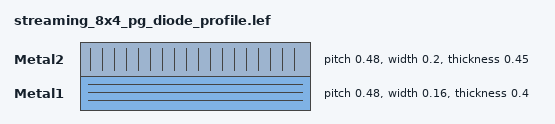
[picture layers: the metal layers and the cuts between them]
LAYER Metal1
  TYPE		ROUTING ;
  DIRECTION	HORIZONTAL ;
  PITCH		0.48 0.42 ;
  OFFSET	0.0 0.0 ;
  WIDTH		0.16 ;
  MAXWIDTH	30 ;
  AREA		0.09 ;
  MINIMUMDENSITY        35.0 ;
  MAXIMUMDENSITY        60.0 ;
  DENSITYCHECKSTEP 100 ;
  DENSITYCHECKWINDOW 200 200 ;
  SPACINGTABLE
  PARALLELRUNLENGTH 0.00    1.00    10.00
  WIDTH 0.00        0.18    0.18    0.18
  WIDTH 0.30        0.18    0.22    0.22
  WIDTH 10.0        0.18    0.22    0.60 ;
  MINIMUMCUT 2 WIDTH 1.4 ;
  HEIGHT 0.930 ;
  #CURRENTDEN 0 ;
  THICKNESS 0.40 ;
  ANTENNACUMAREARATIO 200 ;
  ANTENNACUMDIFFAREARATIO PWL ( ( 0 200 ) ( 0.159 200 ) ( 0.16  3200 ) ( 100 2000000 ) ) ;
  RESISTANCE RPERSQ 0.135 ;
  CAPACITANCE  CPERSQDIST 3.49E-05 ;
  EDGECAPACITANCE  3.16E-05 ;
  DCCURRENTDENSITY AVERAGE 1 ;

END Metal1


LAYER Metal2
  TYPE		ROUTING ;
  DIRECTION	VERTICAL ;
  PITCH		0.48 0.42 ;
  OFFSET	0.0 0.0 ;
  WIDTH		0.20 ;
  MAXWIDTH	30 ;
  MINIMUMDENSITY        35.0 ;
  MAXIMUMDENSITY        60.0 ;
  DENSITYCHECKSTEP 100 ;
  DENSITYCHECKWINDOW 200 200 ;
  SPACINGTABLE
  PARALLELRUNLENGTH 0.00    1.00    10.00
  WIDTH 0.00        0.21    0.21    0.21
  WIDTH 0.39        0.21    0.24    0.24
  WIDTH 10.0        0.21    0.24    0.60 ;
  MINIMUMCUT 2 WIDTH 1.4 ;
  AREA      0.144 ;
  HEIGHT 1.880 ;
  #CURRENTDEN 0 ;
  THICKNESS 0.450 ;
  ANTENNACUMAREARATIO 200 ;
  ANTENNACUMDIFFAREARATIO PWL ( ( 0 200 ) ( 0.159 200 ) ( 0.16  3200 ) ( 100 2000000 ) ) ;
  RESISTANCE RPERSQ 0.103 ;
  CAPACITANCE  CPERSQDIST 1.81E-05 ;
  EDGECAPACITANCE  4.47E-05 ;
  DCCURRENTDENSITY AVERAGE 2 ;
END Metal2


Via  Via1_YY DEFAULT
  RESISTANCE  20.00 ;
  LAYER Metal1 ;
      RECT -0.105 -0.145 0.105 0.145 ;
    LAYER Via1 ;
      RECT -0.095 -0.095 0.095 0.095 ;
    LAYER Metal2 ;
      RECT -0.1 -0.145 0.1 0.145 ;
  END Via1_YY


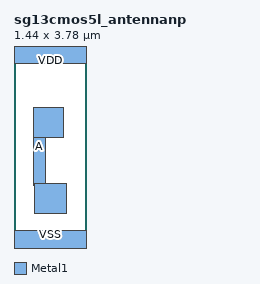
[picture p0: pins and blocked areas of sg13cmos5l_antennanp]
MACRO sg13cmos5l_antennanp
  CLASS CORE ANTENNACELL ;
  ORIGIN 0 0 ;
  FOREIGN sg13cmos5l_antennanp 0 0 ;
  SIZE 1.44 BY 3.78 ;
  SYMMETRY X Y ;
  SITE CoreSite ;
  PIN VDD
    DIRECTION INOUT ;
    USE POWER ;
    SHAPE ABUTMENT ;
    NETEXPR "VDD VDD!" ;
    PORT
      LAYER Metal1 ;
        RECT 0 3.56 1.44 4 ;
    END
  END VDD
  PIN VSS
    DIRECTION INOUT ;
    USE GROUND ;
    SHAPE ABUTMENT ;
    NETEXPR "VSS VSS!" ;
    PORT
      LAYER Metal1 ;
        RECT 0 -0.22 1.44 0.22 ;
    END
  END VSS
  PIN A
    DIRECTION INPUT ;
    USE SIGNAL ;
    ANTENNADIFFAREA 2.0154 LAYER Metal1 ;
    PORT
      LAYER Metal1 ;
        RECT 0.405 0.57 1.05 1.16 ;
        RECT 0.38 2.08 0.98 2.68 ;
        RECT 0.38 1.13 0.63 2.68 ;
    END
  END A
  PROPERTY CatenaDesignType "deviceLevel" ;
END sg13cmos5l_antennanp

